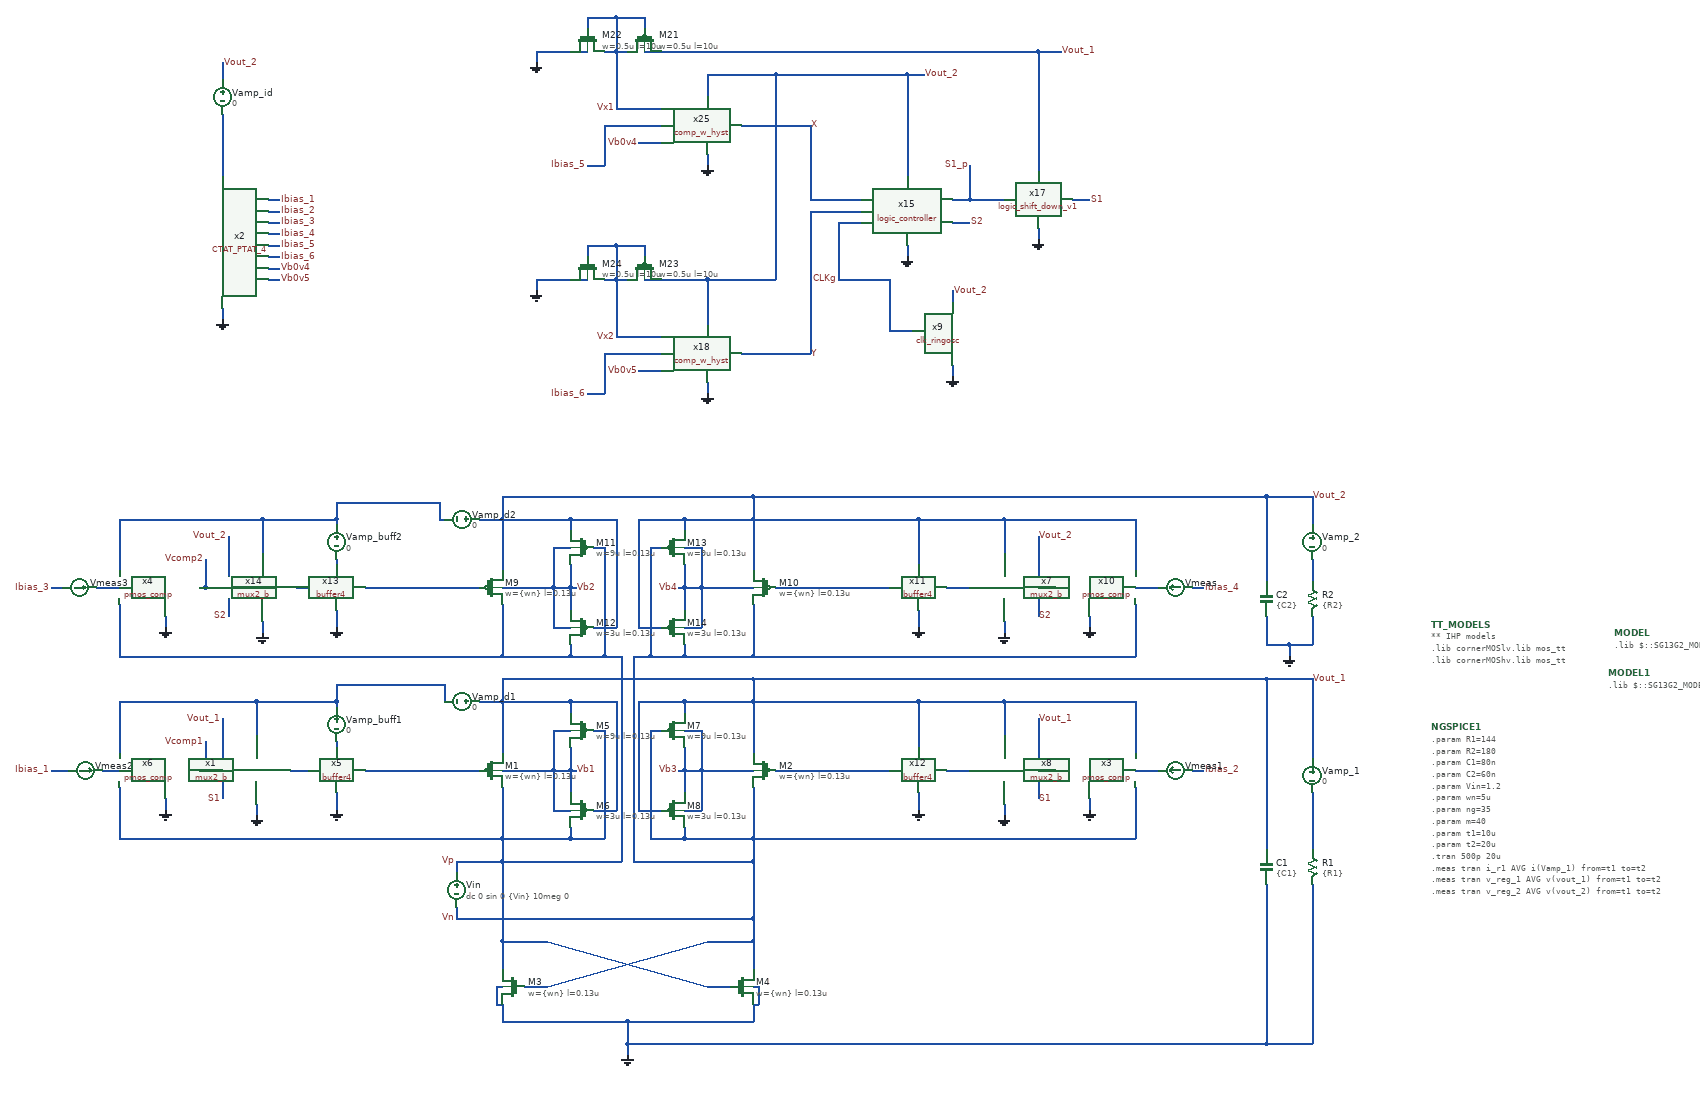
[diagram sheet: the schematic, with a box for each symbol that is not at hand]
v {xschem version=3.4.6 file_version=1.2}
G {}
K {}
V {}
S {}
E {}
P 4 1 1280 -1410 {}
P 4 1 390 -1840 {}
P 4 1 2680 -350 {}
P 4 1 770 -1640 {}
P 4 1 1830 -810 {}
N 1160 -690 1180 -690 {lab=Vp}
N 1160 -550 1200 -550 {lab=Vout_1}
N 1260 -690 1280 -690 {lab=Vn}
N 1240 -550 1280 -550 {lab=Vout_1}
N 1320 -620 1320 -580 {lab=Vb3}
N 1320 -660 1320 -620 {lab=Vb3}
N 1120 -620 1120 -580 {lab=Vb1}
N 1090 -620 1120 -620 {lab=Vb1}
N 1120 -660 1120 -620 {lab=Vb1}
N 1180 -690 1180 -500 {lab=Vp}
N 1000 -590 1000 -500 {lab=Vp}
N 1440 -590 1440 -500 {lab=Vn}
N 1260 -690 1260 -500 {lab=Vn}
N 1240 -740 1240 -550 {lab=Vout_1}
N 1200 -740 1200 -550 {lab=Vout_1}
N 1220 -180 1440 -180 {lab=GND}
N 1440 -320 1440 -270 {lab=Vn}
N 1000 -320 1000 -270 {lab=Vp}
N 1040 -240 1080 -240 {lab=Vn}
N 1360 -240 1400 -240 {lab=Vp}
N 1080 -240 1360 -320 {lab=Vn}
N 1080 -320 1360 -240 {lab=Vp}
N 1000 -320 1080 -320 {lab=Vp}
N 1000 -460 1000 -320 {lab=Vp}
N 1360 -320 1440 -320 {lab=Vn}
N 1440 -360 1440 -320 {lab=Vn}
N 920 -380 920 -360 {lab=Vn}
N 920 -360 1440 -360 {lab=Vn}
N 1440 -460 1440 -360 {lab=Vn}
N 920 -460 1000 -460 {lab=Vp}
N 1000 -500 1000 -460 {lab=Vp}
N 1090 -690 1120 -690 {lab=Vb1}
N 1090 -690 1090 -620 {lab=Vb1}
N 1090 -550 1120 -550 {lab=Vb1}
N 1090 -620 1090 -550 {lab=Vb1}
N 1320 -690 1350 -690 {lab=Vb3}
N 1350 -690 1350 -620 {lab=Vb3}
N 1320 -620 1350 -620 {lab=Vb3}
N 1320 -550 1350 -550 {lab=Vb3}
N 1350 -620 1350 -550 {lab=Vb3}
N 330 -590 330 -500 {lab=Vp}
N 330 -740 330 -650 {lab=#net1}
N 1000 -780 1000 -740 {lab=Vout_1}
N 1000 -780 1440 -780 {lab=Vout_1}
N 1440 -780 1440 -740 {lab=Vout_1}
N 1220 -140 1220 -120 {lab=GND}
N 1000 -180 1220 -180 {lab=GND}
N 2340 -420 2340 -140 {lab=GND}
N 2420 -420 2420 -140 {lab=GND}
N 2340 -140 2420 -140 {lab=GND}
N 2340 -780 2340 -480 {lab=Vout_1}
N 2420 -580 2420 -480 {lab=#net2}
N 2420 -780 2420 -640 {lab=Vout_1}
N 1440 -240 1450 -240 {lab=GND}
N 1450 -240 1450 -210 {lab=GND}
N 1440 -210 1450 -210 {lab=GND}
N 1440 -210 1440 -180 {lab=GND}
N 1000 -210 1000 -180 {lab=GND}
N 990 -240 1000 -240 {lab=GND}
N 990 -240 990 -210 {lab=GND}
N 990 -210 1000 -210 {lab=GND}
N 480 -670 480 -620 {lab=Vcomp1}
N 470 -620 480 -620 {lab=Vcomp1}
N 1120 -620 1130 -620 {lab=Vb1}
N 710 -580 710 -550 {lab=GND}
N 2110 -590 2110 -500 {lab=Vn}
N 2110 -740 2110 -650 {lab=Vout_1}
N 1730 -740 1730 -660 {lab=Vout_1}
N 1730 -580 1730 -550 {lab=GND}
N 1440 -500 2110 -500 {lab=Vn}
N 1160 -1010 1180 -1010 {lab=Vp}
N 1160 -870 1200 -870 {lab=Vout_2}
N 1260 -1010 1280 -1010 {lab=Vn}
N 1240 -870 1280 -870 {lab=Vout_2}
N 1320 -940 1320 -900 {lab=Vb4}
N 1320 -980 1320 -940 {lab=Vb4}
N 1120 -940 1120 -900 {lab=Vb2}
N 1090 -940 1120 -940 {lab=Vb2}
N 1120 -980 1120 -940 {lab=Vb2}
N 1180 -1010 1180 -820 {lab=Vp}
N 1000 -910 1000 -820 {lab=Vp}
N 1440 -910 1440 -820 {lab=Vn}
N 1260 -1010 1260 -820 {lab=Vn}
N 1240 -1060 1240 -870 {lab=Vout_2}
N 1200 -1060 1200 -870 {lab=Vout_2}
N 1090 -1010 1120 -1010 {lab=Vb2}
N 1090 -1010 1090 -940 {lab=Vb2}
N 1090 -870 1120 -870 {lab=Vb2}
N 1090 -940 1090 -870 {lab=Vb2}
N 1320 -1010 1350 -1010 {lab=Vb4}
N 1350 -1010 1350 -940 {lab=Vb4}
N 1320 -940 1350 -940 {lab=Vb4}
N 1320 -870 1350 -870 {lab=Vb4}
N 1350 -940 1350 -870 {lab=Vb4}
N 330 -1060 330 -970 {lab=#net3}
N 480 -990 480 -940 {lab=Vcomp2}
N 470 -940 480 -940 {lab=Vcomp2}
N 1120 -940 1130 -940 {lab=Vb2}
N 710 -900 710 -870 {lab=GND}
N 2110 -910 2110 -820 {lab=Vn}
N 2110 -1060 2110 -970 {lab=Vout_2}
N 1730 -1060 1730 -980 {lab=Vout_2}
N 1730 -900 1730 -870 {lab=GND}
N 1440 -820 2110 -820 {lab=Vn}
N 1000 -460 1210 -460 {lab=Vp}
N 1180 -820 1210 -820 {lab=Vp}
N 1210 -820 1210 -460 {lab=Vp}
N 1230 -820 1260 -820 {lab=Vn}
N 1230 -820 1230 -460 {lab=Vn}
N 1230 -460 1440 -460 {lab=Vn}
N 1440 -500 1440 -460 {lab=Vn}
N 2380 -840 2420 -840 {lab=GND}
N 2380 -840 2380 -820 {lab=GND}
N 2340 -840 2380 -840 {lab=GND}
N 1220 -180 1220 -140 {lab=GND}
N 2420 -890 2420 -840 {lab=GND}
N 2340 -890 2340 -840 {lab=GND}
N 2340 -1100 2340 -950 {lab=Vout_2}
N 2420 -990 2420 -950 {lab=#net4}
N 2420 -1100 2420 -1050 {lab=Vout_2}
N 1000 -1100 1000 -1060 {lab=Vout_2}
N 1440 -1100 2340 -1100 {lab=Vout_2}
N 1440 -1100 1440 -1060 {lab=Vout_2}
N 1000 -1100 1440 -1100 {lab=Vout_2}
N 300 -620 330 -620 {lab=#net5}
N 1440 -780 2340 -780 {lab=Vout_1}
N 2340 -780 2420 -780 {lab=Vout_1}
N 2340 -1100 2420 -1100 {lab=Vout_2}
N 330 -500 1000 -500 {lab=Vp}
N 1220 -140 2340 -140 {lab=GND}
N 1250 -1940 1250 -1920 {lab=Vx1}
N 1150 -1940 1200 -1940 {lab=Vx1}
N 1150 -1940 1150 -1920 {lab=Vx1}
N 1180 -1880 1200 -1880 {lab=Vx1}
N 1200 -1940 1200 -1880 {lab=Vx1}
N 1200 -1940 1250 -1940 {lab=Vx1}
N 1200 -1880 1220 -1880 {lab=Vx1}
N 1200 -1780 1280 -1780 {lab=Vx1}
N 1200 -1880 1200 -1780 {lab=Vx1}
N 1240 -1720 1280 -1720 {lab=Vb0v4}
N 1180 -1750 1180 -1680 {lab=Ibias_5}
N 1180 -1750 1280 -1750 {lab=Ibias_5}
N 1060 -1880 1060 -1860 {lab=GND}
N 1060 -1880 1150 -1880 {lab=GND}
N 1360 -1700 1360 -1680 {lab=GND}
N 1250 -1540 1250 -1520 {lab=Vx2}
N 1150 -1540 1200 -1540 {lab=Vx2}
N 1150 -1540 1150 -1520 {lab=Vx2}
N 1180 -1480 1200 -1480 {lab=Vx2}
N 1200 -1540 1200 -1480 {lab=Vx2}
N 1200 -1540 1250 -1540 {lab=Vx2}
N 1200 -1480 1220 -1480 {lab=Vx2}
N 1200 -1380 1280 -1380 {lab=Vx2}
N 1200 -1480 1200 -1380 {lab=Vx2}
N 1240 -1320 1280 -1320 {lab=Vb0v5}
N 1180 -1350 1180 -1280 {lab=Ibias_6}
N 1180 -1350 1280 -1350 {lab=Ibias_6}
N 1060 -1480 1060 -1460 {lab=GND}
N 1060 -1480 1150 -1480 {lab=GND}
N 1360 -1300 1360 -1280 {lab=GND}
N 1360 -1840 1360 -1800 {lab=Vout_2}
N 1710 -1540 1710 -1520 {lab=GND}
N 1540 -1620 1630 -1620 {lab=X}
N 1420 -1350 1540 -1350 {lab=Y}
N 1480 -1840 1480 -1480 {lab=Vout_2}
N 1420 -1750 1540 -1750 {lab=X}
N 1540 -1750 1540 -1620 {lab=X}
N 1540 -1600 1540 -1350 {lab=Y}
N 1540 -1600 1630 -1600 {lab=Y}
N 1710 -1840 1740 -1840 {lab=Vout_2}
N 1790 -1580 1820 -1580 {lab=S2}
N 1820 -1620 1880 -1620 {lab=S1_p}
N 1940 -1880 1940 -1670 {lab=Vout_1}
N 1940 -1880 1980 -1880 {lab=Vout_1}
N 1940 -1570 1940 -1550 {lab=GND}
N 2000 -1620 2030 -1620 {lab=S1}
N 570 -560 570 -540 {lab=GND}
N 570 -740 710 -740 {lab=#net1}
N 510 -600 510 -570 {lab=S1}
N 510 -710 510 -640 {lab=Vout_1}
N 1880 -740 2110 -740 {lab=Vout_1}
N 580 -1060 710 -1060 {lab=#net3}
N 1880 -880 1880 -860 {lab=GND}
N 1940 -920 1940 -890 {lab=S2}
N 1940 -1030 1940 -960 {lab=Vout_2}
N 1880 -1060 2110 -1060 {lab=Vout_2}
N 1360 -1480 1480 -1480 {lab=Vout_2}
N 1250 -1880 1940 -1880 {lab=Vout_1}
N 1820 -1680 1820 -1620 {lab=S1_p}
N 1790 -1620 1820 -1620 {lab=S1_p}
N 2110 -620 2150 -620 {lab=#net6}
N 2110 -940 2150 -940 {lab=#net7}
N 290 -940 330 -940 {lab=#net8}
N 1150 -1280 1180 -1280 {lab=Ibias_6}
N 1150 -1680 1180 -1680 {lab=Ibias_5}
N 960 -1060 1000 -1060 {lab=Vout_2}
N 960 -740 1000 -740 {lab=Vout_1}
N 710 -1060 710 -1050 {lab=#net3}
N 710 -990 710 -980 {lab=#net9}
N 710 -670 710 -660 {lab=#net10}
N 710 -740 710 -730 {lab=#net1}
N 890 -1060 900 -1060 {lab=#net3}
N 890 -1090 890 -1060 {lab=#net3}
N 710 -1090 710 -1060 {lab=#net3}
N 900 -770 900 -740 {lab=#net1}
N 710 -770 710 -740 {lab=#net1}
N 2210 -940 2230 -940 {lab=Ibias_4}
N 2210 -620 2230 -620 {lab=Ibias_2}
N 1310 -940 1320 -940 {lab=Vb4}
N 1310 -620 1320 -620 {lab=Vb3}
N 1360 -1480 1360 -1400 {lab=Vout_2}
N 1250 -1480 1360 -1480 {lab=Vout_2}
N 1360 -1840 1480 -1840 {lab=Vout_2}
N 1710 -1840 1710 -1660 {lab=Vout_2}
N 1480 -1840 1710 -1840 {lab=Vout_2}
N 1120 -1060 1200 -1060 {lab=Vout_2}
N 1320 -1060 1440 -1060 {lab=Vout_2}
N 1120 -820 1180 -820 {lab=Vp}
N 1120 -740 1200 -740 {lab=Vout_1}
N 1320 -740 1440 -740 {lab=Vout_1}
N 1120 -500 1180 -500 {lab=Vp}
N 1320 -500 1440 -500 {lab=Vn}
N 1320 -820 1440 -820 {lab=Vn}
N 1590 -1580 1630 -1580 {lab=CLKg}
N 1590 -1480 1680 -1480 {lab=CLKg}
N 1590 -1580 1590 -1480 {lab=CLKg}
N 210 -620 240 -620 {lab=Ibias_1}
N 210 -940 230 -940 {lab=Ibias_3}
N 510 -1430 510 -1410 {lab=GND}
N 590 -1620 610 -1620 {lab=Ibias_1}
N 590 -1600 610 -1600 {lab=Ibias_2}
N 590 -1580 610 -1580 {lab=Ibias_3}
N 590 -1560 610 -1560 {lab=Ibias_4}
N 590 -1540 610 -1540 {lab=Ibias_5}
N 590 -1520 610 -1520 {lab=Ibias_6}
N 590 -1500 610 -1500 {lab=Vb0v4}
N 590 -1480 610 -1480 {lab=Vb0v5}
N 510 -1860 510 -1830 {lab=Vout_2}
N 510 -1770 510 -1660 {lab=#net11}
N 410 -890 410 -870 {lab=GND}
N 410 -570 410 -550 {lab=GND}
N 2030 -570 2030 -550 {lab=GND}
N 2030 -890 2030 -870 {lab=GND}
N 1680 -1480 1680 -1390 {lab=CLKg}
N 1680 -1390 1720 -1390 {lab=CLKg}
N 1790 -1460 1790 -1440 {lab=Vout_2}
N 1790 -1330 1790 -1310 {lab=GND}
N 580 -880 580 -860 {lab=GND}
N 520 -920 520 -890 {lab=S2}
N 520 -1030 520 -960 {lab=Vout_2}
N 710 -1090 890 -1090 {lab=#net3}
N 710 -770 900 -770 {lab=#net1}
N 1880 -560 1880 -540 {lab=GND}
N 1940 -600 1940 -570 {lab=S1}
N 1940 -710 1940 -640 {lab=Vout_1}
N 1440 -740 1730 -740 {lab=Vout_1}
N 1440 -1060 1730 -1060 {lab=Vout_2}
N 1120 -740 1120 -720 {lab=Vout_1}
N 1000 -740 1120 -740 {lab=Vout_1}
N 1120 -520 1120 -500 {lab=Vp}
N 1000 -500 1120 -500 {lab=Vp}
N 1320 -520 1320 -500 {lab=Vn}
N 1260 -500 1320 -500 {lab=Vn}
N 1320 -740 1320 -720 {lab=Vout_1}
N 1240 -740 1320 -740 {lab=Vout_1}
N 1120 -1060 1120 -1040 {lab=Vout_2}
N 1000 -1060 1120 -1060 {lab=Vout_2}
N 1120 -840 1120 -820 {lab=Vp}
N 1000 -820 1120 -820 {lab=Vp}
N 1320 -1060 1320 -1040 {lab=Vout_2}
N 1240 -1060 1320 -1060 {lab=Vout_2}
N 1320 -840 1320 -820 {lab=Vn}
N 1260 -820 1320 -820 {lab=Vn}
N 330 -910 330 -820 {lab=Vp}
N 330 -820 1000 -820 {lab=Vp}
N 920 -460 920 -440 {lab=Vp}
N 1000 -940 1090 -940 {lab=Vb2}
N 1000 -1060 1000 -970 {lab=Vout_2}
N 1350 -940 1440 -940 {lab=Vb4}
N 1440 -1060 1440 -970 {lab=Vout_2}
N 1000 -620 1090 -620 {lab=Vb1}
N 1000 -740 1000 -650 {lab=Vout_1}
N 1440 -740 1440 -650 {lab=Vout_1}
N 1350 -620 1440 -620 {lab=Vb3}
N 480 -940 520 -940 {lab=Vcomp2}
N 640 -940 660 -940 {lab=#net12}
N 580 -1060 580 -1000 {lab=#net3}
N 330 -1060 580 -1060 {lab=#net3}
N 760 -940 960 -940 {lab=#net13}
N 480 -620 510 -620 {lab=Vcomp1}
N 630 -620 660 -620 {lab=#net14}
N 760 -620 960 -620 {lab=#net15}
N 1940 -620 1970 -620 {lab=#net16}
N 1780 -620 1820 -620 {lab=#net17}
N 1480 -620 1680 -620 {lab=#net18}
N 1940 -940 1970 -940 {lab=#net19}
N 1780 -940 1820 -940 {lab=#net20}
N 1480 -940 1680 -940 {lab=#net21}
N 570 -740 570 -680 {lab=#net1}
N 330 -740 570 -740 {lab=#net1}
N 1880 -1060 1880 -1000 {lab=Vout_2}
N 1730 -1060 1880 -1060 {lab=Vout_2}
N 1880 -740 1880 -680 {lab=Vout_1}
N 1730 -740 1880 -740 {lab=Vout_1}
C {sg13g2_pr/sg13_lv_pmos.sym} 980 -620 0 0 {name=M1
l=0.13u
w=\{wn\}
ng=\{ng\}
m=\{5*m\}
model=sg13_lv_pmos
spiceprefix=X
}
C {sg13g2_pr/sg13_lv_pmos.sym} 1460 -620 0 1 {name=M2
l=0.13u
w=\{wn\}
ng=\{ng\}
m=\{5*m\}
model=sg13_lv_pmos
spiceprefix=X
}
C {sg13g2_pr/sg13_lv_nmos.sym} 1020 -240 0 1 {name=M3
l=0.13u
w=\{wn\}
ng=\{ng\}
m=\{3*m\}
model=sg13_lv_nmos
spiceprefix=X
}
C {sg13g2_pr/sg13_lv_nmos.sym} 1420 -240 0 0 {name=M4
l=0.13u
w=\{wn\}
ng=\{ng\}
m=\{3*m\}
model=sg13_lv_nmos
spiceprefix=X
}
C {sg13g2_pr/sg13_lv_pmos.sym} 1140 -690 0 1 {name=M5
l=0.13u
w=9u
ng=1
m=1
model=sg13_lv_pmos
spiceprefix=X
}
C {sg13g2_pr/sg13_lv_pmos.sym} 1140 -550 2 0 {name=M6
l=0.13u
w=3u
ng=1
m=1
model=sg13_lv_pmos
spiceprefix=X
}
C {sg13g2_pr/sg13_lv_pmos.sym} 1300 -690 0 0 {name=M7
l=0.13u
w=9u
ng=1
m=1
model=sg13_lv_pmos
spiceprefix=X
}
C {sg13g2_pr/sg13_lv_pmos.sym} 1300 -550 2 1 {name=M8
l=0.13u
w=3u
ng=1
m=1
model=sg13_lv_pmos
spiceprefix=X
}
C {vsource.sym} 920 -410 0 1 {name=Vin value="dc 0 sin 0 \{Vin\} 10meg 0" savecurrent=false}
C {lab_pin.sym} 920 -460 0 0 {name=p1 sig_type=std_logic lab=Vp}
C {lab_pin.sym} 920 -360 0 0 {name=p2 sig_type=std_logic lab=Vn}
C {capa.sym} 2340 -450 0 0 {name=C1
m=1
value=\{C1\}
footprint=1206
device="ceramic capacitor"}
C {res.sym} 2420 -450 0 0 {name=R1
value=\{R1\}
footprint=1206
device=resistor
m=1}
C {vsource.sym} 2420 -610 0 0 {name=Vamp_1 value=0 savecurrent=false}
C {lab_pin.sym} 2420 -780 0 1 {name=p3 sig_type=std_logic lab=Vout_1}
C {gnd.sym} 1220 -120 0 0 {name=l3 lab=GND}
C {lab_pin.sym} 480 -670 0 0 {name=p4 sig_type=std_logic lab=Vcomp1}
C {lab_pin.sym} 1130 -620 0 1 {name=p6 sig_type=std_logic lab=Vb1}
C {gnd.sym} 410 -550 0 0 {name=l4 lab=GND}
C {gnd.sym} 710 -550 0 0 {name=l5 lab=GND}
C {code_shown.sym} 2630 -875 0 0 {
name=TT_MODELS
only_toplevel=true
value="
** IHP models
.lib cornerMOSlv.lib mos_tt
.lib cornerMOShv.lib mos_tt
"
spice_ignore=false
      }
C {gnd.sym} 2030 -550 0 1 {name=l6 lab=GND}
C {gnd.sym} 1730 -550 0 1 {name=l7 lab=GND}
C {sg13g2_pr/sg13_lv_pmos.sym} 980 -940 0 0 {name=M9
l=0.13u
w=\{wn\}
ng=\{ng\}
m=\{5*m\}
model=sg13_lv_pmos
spiceprefix=X
}
C {sg13g2_pr/sg13_lv_pmos.sym} 1460 -940 0 1 {name=M10
l=0.13u
w=\{wn\}
ng=\{ng\}
m=\{5*m\}
model=sg13_lv_pmos
spiceprefix=X
}
C {sg13g2_pr/sg13_lv_pmos.sym} 1140 -1010 0 1 {name=M11
l=0.13u
w=9u
ng=1
m=1
model=sg13_lv_pmos
spiceprefix=X
}
C {sg13g2_pr/sg13_lv_pmos.sym} 1140 -870 2 0 {name=M12
l=0.13u
w=3u
ng=1
m=1
model=sg13_lv_pmos
spiceprefix=X
}
C {sg13g2_pr/sg13_lv_pmos.sym} 1300 -1010 0 0 {name=M13
l=0.13u
w=9u
ng=1
m=1
model=sg13_lv_pmos
spiceprefix=X
}
C {sg13g2_pr/sg13_lv_pmos.sym} 1300 -870 2 1 {name=M14
l=0.13u
w=3u
ng=1
m=1
model=sg13_lv_pmos
spiceprefix=X
}
C {lab_pin.sym} 480 -990 0 0 {name=p11 sig_type=std_logic lab=Vcomp2}
C {lab_pin.sym} 1130 -940 0 1 {name=p14 sig_type=std_logic lab=Vb2}
C {gnd.sym} 410 -870 0 0 {name=l11 lab=GND}
C {gnd.sym} 710 -870 0 0 {name=l12 lab=GND}
C {gnd.sym} 2030 -870 0 1 {name=l14 lab=GND}
C {gnd.sym} 1730 -870 0 1 {name=l15 lab=GND}
C {capa.sym} 2340 -920 0 0 {name=C2
m=1
value=\{C2\}
footprint=1206
device="ceramic capacitor"}
C {res.sym} 2420 -920 0 0 {name=R2
value=\{R2\}
footprint=1206
device=resistor
m=1}
C {vsource.sym} 2420 -1020 0 0 {name=Vamp_2 value=0 savecurrent=false}
C {gnd.sym} 2380 -820 0 1 {name=l18 lab=GND}
C {lab_pin.sym} 2420 -1100 0 1 {name=p20 sig_type=std_logic lab=Vout_2}
C {sg13g2_pr/sg13_lv_pmos.sym} 1250 -1900 1 0 {name=M21
l=10u
w=0.5u
ng=1
m=19
model=sg13_lv_pmos
spiceprefix=X
}
C {sg13g2_pr/sg13_lv_nmos.sym} 1150 -1900 1 0 {name=M22
l=10u
w=0.5u
ng=1
m=1
model=sg13_lv_nmos
spiceprefix=X
}
C {gnd.sym} 1060 -1860 0 0 {name=l22 lab=GND}
C {gnd.sym} 1360 -1680 0 0 {name=l25 lab=GND}
C {sg13g2_pr/sg13_lv_pmos.sym} 1250 -1500 1 0 {name=M23
l=10u
w=0.5u
ng=1
m=10
model=sg13_lv_pmos
spiceprefix=X
}
C {sg13g2_pr/sg13_lv_nmos.sym} 1150 -1500 1 0 {name=M24
l=10u
w=0.5u
ng=1
m=1
model=sg13_lv_nmos
spiceprefix=X
}
C {gnd.sym} 1060 -1460 0 0 {name=l26 lab=GND}
C {lab_pin.sym} 1980 -1880 0 1 {name=p27 sig_type=std_logic lab=Vout_1}
C {lab_pin.sym} 1740 -1840 0 1 {name=p28 sig_type=std_logic lab=Vout_2}
C {gnd.sym} 1710 -1520 0 0 {name=l30 lab=GND}
C {lab_pin.sym} 1820 -1580 0 1 {name=p26 sig_type=std_logic lab=S2}
C {gnd.sym} 1940 -1550 0 0 {name=l32 lab=GND}
C {lab_pin.sym} 2030 -1620 0 1 {name=p29 sig_type=std_logic lab=S1}
C {gnd.sym} 570 -540 0 0 {name=l33 lab=GND}
C {lab_pin.sym} 510 -710 0 0 {name=p30 sig_type=std_logic lab=Vout_1}
C {lab_pin.sym} 510 -570 0 0 {name=p31 sig_type=std_logic lab=S1}
C {gnd.sym} 580 -860 0 0 {name=l35 lab=GND}
C {lab_pin.sym} 520 -1030 0 0 {name=p34 sig_type=std_logic lab=Vout_2}
C {lab_pin.sym} 520 -890 0 0 {name=p35 sig_type=std_logic lab=S2}
C {gnd.sym} 1880 -860 0 1 {name=l36 lab=GND}
C {lab_pin.sym} 1940 -890 0 1 {name=p37 sig_type=std_logic lab=S2}
C {lab_pin.sym} 1200 -1780 0 0 {name=p38 sig_type=std_logic lab=Vx1}
C {lab_pin.sym} 1200 -1380 0 0 {name=p39 sig_type=std_logic lab=Vx2}
C {lab_pin.sym} 1540 -1350 0 1 {name=p41 sig_type=std_logic lab=Y}
C {lab_pin.sym} 1540 -1750 0 1 {name=p42 sig_type=std_logic lab=X}
C {lab_pin.sym} 1820 -1680 0 0 {name=p45 sig_type=std_logic lab=S1_p}
C {gnd.sym} 1360 -1280 0 0 {name=l38 lab=GND}
C {lab_pin.sym} 210 -620 0 0 {name=p57 sig_type=std_logic lab=Ibias_1}
C {lab_pin.sym} 2230 -620 0 1 {name=p58 sig_type=std_logic lab=Ibias_2}
C {lab_pin.sym} 2230 -940 0 1 {name=p59 sig_type=std_logic lab=Ibias_4}
C {lab_pin.sym} 210 -940 0 0 {name=p60 sig_type=std_logic lab=Ibias_3}
C {lab_pin.sym} 1150 -1680 0 0 {name=p61 sig_type=std_logic lab=Ibias_5}
C {lab_pin.sym} 1150 -1280 0 0 {name=p62 sig_type=std_logic lab=Ibias_6}
C {vsource.sym} 930 -1060 1 1 {name=Vamp_d2 value=0 savecurrent=false}
C {vsource.sym} 930 -740 1 1 {name=Vamp_d1 value=0 savecurrent=false}
C {vsource.sym} 710 -1020 0 1 {name=Vamp_buff2 value=0 savecurrent=false}
C {vsource.sym} 710 -700 0 1 {name=Vamp_buff1 value=0 savecurrent=false}
C {/shared/designs/SSDOR_1.2V_v2/components/comp_w_hyst/comp_w_hyst.sym} 1360 -1750 0 0 {name=x25}
C {/shared/designs/SSDOR_1.2V_v2/components/logic_contorller/logic_controller.sym} 1710 -1600 0 0 {name=x15}
C {/shared/designs/SSDOR_1.2V_v2/components/logic_shift_down_v1/logic_shift_down_v1.sym} 1940 -1620 0 0 {name=x17}
C {/shared/designs/SSDOR_1.2V_v2/components/comp_w_hyst/comp_w_hyst.sym} 1360 -1350 0 0 {name=x18}
C {ammeter.sym} 2180 -940 1 0 {name=Vmeas savecurrent=true spice_ignore=0}
C {ammeter.sym} 2180 -620 1 0 {name=Vmeas1 savecurrent=true spice_ignore=0}
C {devices/code_shown.sym} 2950 -860 0 0 {name=MODEL only_toplevel=true
format="tcleval( @value )"
value="
.lib $::SG13G2_MODELS/cornerRES.lib res_typ
"}
C {lab_pin.sym} 1310 -940 0 0 {name=p51 sig_type=std_logic lab=Vb4}
C {lab_pin.sym} 1310 -620 0 0 {name=p63 sig_type=std_logic lab=Vb3}
C {devices/code_shown.sym} 2940 -790 0 0 {name=MODEL1 only_toplevel=true
format="tcleval( @value )"
value="
.lib $::SG13G2_MODELS/cornerCAP.lib cap_typ
"}
C {lab_pin.sym} 1590 -1480 0 0 {name=p12 sig_type=std_logic lab=CLKg}
C {ammeter.sym} 270 -620 3 1 {name=Vmeas2 savecurrent=true spice_ignore=0}
C {ammeter.sym} 260 -940 3 1 {name=Vmeas3 savecurrent=true spice_ignore=0}
C {lab_pin.sym} 1940 -1030 0 1 {name=p7 sig_type=std_logic lab=Vout_2}
C {vsource.sym} 510 -1800 0 1 {name=Vamp_id value=0 savecurrent=false}
C {lab_pin.sym} 610 -1520 0 1 {name=p24 sig_type=std_logic lab=Ibias_6}
C {gnd.sym} 510 -1410 0 0 {name=l1 lab=GND}
C {lab_pin.sym} 610 -1620 0 1 {name=p8 sig_type=std_logic lab=Ibias_1}
C {lab_pin.sym} 610 -1600 0 1 {name=p10 sig_type=std_logic lab=Ibias_2}
C {lab_pin.sym} 610 -1580 0 1 {name=p13 sig_type=std_logic lab=Ibias_3}
C {lab_pin.sym} 610 -1560 0 1 {name=p15 sig_type=std_logic lab=Ibias_4}
C {lab_pin.sym} 610 -1540 0 1 {name=p16 sig_type=std_logic lab=Ibias_5}
C {lab_pin.sym} 510 -1860 0 1 {name=p5 sig_type=std_logic lab=Vout_2}
C {/shared/designs/SSDOR_1.2V_v2/components/Ib_4u/CTAT_PTAT/CTAT_PTAT_4.sym} 450 -1410 0 0 {name=x2}
C {/shared/designs/SSDOR_1.2V_v2/components/cgenerator/clk_ringosc.sym} 1830 -1330 0 1 {name=x9}
C {lab_pin.sym} 1790 -1460 0 1 {name=p9 sig_type=std_logic lab=Vout_2}
C {gnd.sym} 1790 -1310 0 0 {name=l8 lab=GND}
C {lab_pin.sym} 610 -1500 0 1 {name=p18 sig_type=std_logic lab=Vb0v4}
C {lab_pin.sym} 610 -1480 0 1 {name=p19 sig_type=std_logic lab=Vb0v5}
C {lab_pin.sym} 1240 -1320 0 0 {name=p21 sig_type=std_logic lab=Vb0v5}
C {lab_pin.sym} 1240 -1720 0 0 {name=p22 sig_type=std_logic lab=Vb0v4}
C {/shared/designs/SSDOR_1.2V_v2/components/pmos_comp/pmos_comp.sym} 310 -870 0 0 {name=x4}
C {/shared/designs/SSDOR_1.2V_v2/components/pmos_comp/pmos_comp.sym} 310 -550 0 0 {name=x6}
C {/shared/designs/SSDOR_1.2V_v2/components/pmos_comp/pmos_comp.sym} 2130 -870 0 1 {name=x10}
C {/shared/designs/SSDOR_1.2V_v2/components/pmos_comp/pmos_comp.sym} 2130 -550 0 1 {name=x3}
C {gnd.sym} 1880 -540 0 1 {name=l2 lab=GND}
C {lab_pin.sym} 1940 -710 0 1 {name=p17 sig_type=std_logic lab=Vout_1}
C {lab_pin.sym} 1940 -570 0 1 {name=p23 sig_type=std_logic lab=S1}
C {/shared/designs/SSDOR_1.2V_v2/components/buffer4/buffer4.sym} 640 -860 0 0 {name=x13 wn=1u}
C {/shared/designs/SSDOR_1.2V_v2/components/buffer4/buffer4.sym} 640 -540 0 0 {name=x5 wn=1u}
C {/shared/designs/SSDOR_1.2V_v2/components/buffer4/buffer4.sym} 1800 -540 0 1 {name=x12 wn=1u}
C {/shared/designs/SSDOR_1.2V_v2/components/buffer4/buffer4.sym} 1800 -860 0 1 {name=x11 wn=1u}
C {/shared/designs/SSDOR_1.2V_v2/components/mux2_b/mux2_b.sym} 580 -940 0 0 {name=x14}
C {/shared/designs/SSDOR_1.2V_v2/components/mux2_b/mux2_b.sym} 570 -620 0 0 {name=x1}
C {/shared/designs/SSDOR_1.2V_v2/components/mux2_b/mux2_b.sym} 1880 -620 0 1 {name=x8}
C {/shared/designs/SSDOR_1.2V_v2/components/mux2_b/mux2_b.sym} 1880 -940 0 1 {name=x7}
C {code_shown.sym} 2630 -695 0 0 {name=NGSPICE1
only_toplevel=false
value="
.param R1=144
.param R2=180
.param C1=80n
.param C2=60n
.param Vin=1.2
.param wn=5u
.param ng=35
.param m=40
.param t1=10u
.param t2=20u
.tran 500p 20u
.meas tran i_r1 AVG i(Vamp_1) from=t1 to=t2
.meas tran v_reg_1 AVG v(vout_1) from=t1 to=t2
.meas tran v_reg_2 AVG v(vout_2) from=t1 to=t2
.meas tran p_out_1 AVG par('((v(Vout_1)**2)/R1)') from=t1 to=t2
.meas tran p_out_2 AVG par('((v(Vout_2)**2)/R2)') from=t1 to=t2
.meas tran p_out AVG par('((v(Vout_1)**2)/R1)+((v(Vout_2)**2)/R2)') from=t1 to=t2
.meas tran p_in AVG par('-(v(Vp)-v(Vn))*i(Vin)') from=t1 to=t2
*.meas tran p_d1 AVG par('v(Vout_1)*(i(Vamp_gate1)+i(Vamp_buff1))*2') from=t1 to=t2
*.meas tran p_d2 AVG par('v(Vout_2)*(i(Vamp_gate2)+i(Vamp_buff2))*2') from=t1 to=t2
.meas tran p_id AVG par('v(Vout_2)*i(Vamp_id)') from=t1 to=t2
*.meas tran p_active_diodes param='(p_d1+p_d2)/p_in*100'
.meas tran p_id_percent param='p_id/p_in*100'
.meas tran i_driver1 AVG par('i(Vamp_d1)') from=t1 to=t2
.meas tran i_driver2 AVG par('i(Vamp_d2)') from=t1 to=t2
.meas tran PCE param='p_out/p_in' from=t1 to=t2
.meas tran VCR_1 param='v_reg_1/Vin'
.meas tran VCR_2 param='v_reg_2/Vin'
.save all
"}
